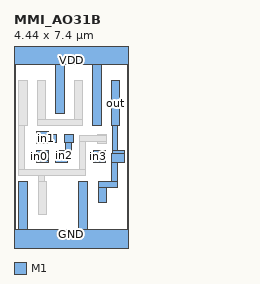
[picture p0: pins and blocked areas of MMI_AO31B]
MACRO MMI_AO31B
	CLASS CORE ;
	FOREIGN MMI_AO31B 0 0 ;
	SIZE 4.44 BY 7.4 ;
	SYMMETRY X Y ;
	SITE CORE1 ;
	PIN out
		DIRECTION output ;
		USE SIGNAL ;
		PORT
			LAYER M1 ;
			RECT 3.78 4.53 4.12 6.29 ;
			LAYER M1 ;
			RECT 3.82 3.555 4.05 4.53 ;
			LAYER M1 ;
			RECT 3.82 3.445 4.295 3.555 ;
			LAYER M1 ;
			RECT 3.785 3.105 4.295 3.445 ;
			LAYER M1 ;
			RECT 3.785 2.36 4.015 3.105 ;
			LAYER M1 ;
			RECT 3.28 2.13 4.015 2.36 ;
			LAYER M1 ;
			RECT 3.28 1.52 3.62 2.13 ;
		END
		AntennaDiffArea 1.3248 ;
	END out
	PIN in1
		DIRECTION input ;
		USE SIGNAL ;
		PORT
			LAYER M1 ;
			RECT 0.885 4.2 1.335 4.295 ;
			LAYER M1 ;
			RECT 0.885 3.86 1.64 4.2 ;
			LAYER M1 ;
			RECT 0.885 3.845 1.335 3.86 ;
		END
		AntennaGateArea 0.5796 ;
	END in1
	PIN GND
		DIRECTION inout ;
		USE GROUND ;
		PORT
			LAYER M1 ;
			RECT 0.18 0.5 0.52 2.36 ;
			LAYER M1 ;
			RECT 2.52 0.5 2.86 2.36 ;
			LAYER M1 ;
			RECT 0 -0.5 4.44 0.5 ;
		END
	END GND
	PIN in2
		DIRECTION input ;
		USE SIGNAL ;
		PORT
			LAYER M1 ;
			RECT 1.97 3.86 2.31 4.2 ;
			LAYER M1 ;
			RECT 2.025 3.555 2.255 3.86 ;
			LAYER M1 ;
			RECT 1.625 3.215 2.255 3.555 ;
			LAYER M1 ;
			RECT 1.625 3.105 2.075 3.215 ;
		END
		AntennaGateArea 0.5796 ;
	END in2
	PIN VDD
		DIRECTION inout ;
		USE POWER ;
		PORT
			LAYER M1 ;
			RECT 0 6.9 4.44 7.9 ;
			LAYER M1 ;
			RECT 1.62 5.01 1.96 6.9 ;
			LAYER M1 ;
			RECT 3.06 4.53 3.4 6.9 ;
		END
	END VDD
	PIN in3
		DIRECTION input ;
		USE SIGNAL ;
		PORT
			LAYER M1 ;
			RECT 3.105 3.5 3.555 3.555 ;
			LAYER M1 ;
			RECT 3 3.16 3.555 3.5 ;
			LAYER M1 ;
			RECT 3.105 3.105 3.555 3.16 ;
		END
		AntennaGateArea 0.5796 ;
	END in3
	PIN in0
		DIRECTION input ;
		USE SIGNAL ;
		PORT
			LAYER M1 ;
			RECT 0.885 3.5 1.335 3.555 ;
			LAYER M1 ;
			RECT 0.64 3.16 1.335 3.5 ;
			LAYER M1 ;
			RECT 0.885 3.105 1.335 3.16 ;
		END
		AntennaGateArea 0.414 ;
	END in0
	OBS
		LAYER M1 ;
		RECT 0.18 4.53 0.52 6.29 ;
		LAYER M1 ;
		RECT 0.9 4.76 1.24 6.29 ;
		LAYER M1 ;
		RECT 2.34 4.76 2.68 6.29 ;
		LAYER M1 ;
		RECT 0.9 4.53 2.68 4.76 ;
		LAYER M1 ;
		RECT 0.18 2.835 0.41 4.53 ;
		LAYER M1 ;
		RECT 3.25 4.135 3.59 4.19 ;
		LAYER M1 ;
		RECT 2.54 3.905 3.59 4.135 ;
		LAYER M1 ;
		RECT 2.54 2.835 2.77 3.905 ;
		LAYER M1 ;
		RECT 3.25 3.85 3.59 3.905 ;
		LAYER M1 ;
		RECT 0.18 2.605 2.77 2.835 ;
		LAYER M1 ;
		RECT 0.94 2.36 1.17 2.605 ;
		LAYER M1 ;
		RECT 0.94 1.06 1.28 2.36 ;
	END
END MMI_AO31B
